VERSION 5.8 ;
BUSBITCHARS "[]" ;
DIVIDERCHAR "/" ;
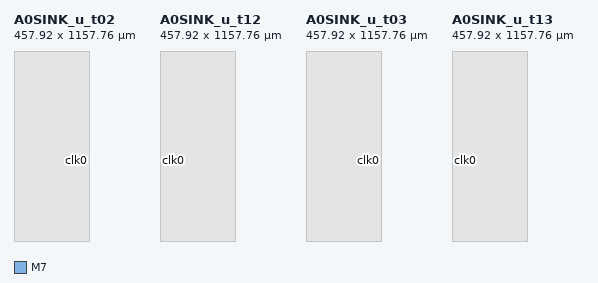
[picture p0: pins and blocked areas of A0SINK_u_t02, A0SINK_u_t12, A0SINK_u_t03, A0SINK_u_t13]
MACRO A0SINK_u_t02
  CLASS BLOCK ;
  ORIGIN 0 0 ;
  SIZE 457.920 BY 1157.760 ;
  SYMMETRY X Y ;
  PIN clk0
    DIRECTION INPUT ;
    USE CLOCK ;
    PORT
      LAYER M7 ;
        RECT 457.380 489.656 457.460 489.736 ;
    END
  END clk0
  OBS
    LAYER M1 ;
      RECT 0 0 457.920 1157.760 ;
    LAYER M2 ;
      RECT 0 0 457.920 1157.760 ;
    LAYER M3 ;
      RECT 0 0 457.920 1157.760 ;
    LAYER M4 ;
      RECT 0 0 457.920 1157.760 ;
    LAYER M5 ;
      RECT 0 0 457.920 1157.760 ;
    LAYER M6 ;
      RECT 0 0 457.920 1157.760 ;
  END
END A0SINK_u_t02
MACRO A0SINK_u_t12
  CLASS BLOCK ;
  ORIGIN 0 0 ;
  SIZE 457.920 BY 1157.760 ;
  SYMMETRY X Y ;
  PIN clk0
    DIRECTION INPUT ;
    USE CLOCK ;
    PORT
      LAYER M7 ;
        RECT 0.460 489.656 0.540 489.736 ;
    END
  END clk0
  OBS
    LAYER M1 ;
      RECT 0 0 457.920 1157.760 ;
    LAYER M2 ;
      RECT 0 0 457.920 1157.760 ;
    LAYER M3 ;
      RECT 0 0 457.920 1157.760 ;
    LAYER M4 ;
      RECT 0 0 457.920 1157.760 ;
    LAYER M5 ;
      RECT 0 0 457.920 1157.760 ;
    LAYER M6 ;
      RECT 0 0 457.920 1157.760 ;
  END
END A0SINK_u_t12
MACRO A0SINK_u_t03
  CLASS BLOCK ;
  ORIGIN 0 0 ;
  SIZE 457.920 BY 1157.760 ;
  SYMMETRY X Y ;
  PIN clk0
    DIRECTION INPUT ;
    USE CLOCK ;
    PORT
      LAYER M7 ;
        RECT 457.380 489.656 457.460 489.736 ;
    END
  END clk0
  OBS
    LAYER M1 ;
      RECT 0 0 457.920 1157.760 ;
    LAYER M2 ;
      RECT 0 0 457.920 1157.760 ;
    LAYER M3 ;
      RECT 0 0 457.920 1157.760 ;
    LAYER M4 ;
      RECT 0 0 457.920 1157.760 ;
    LAYER M5 ;
      RECT 0 0 457.920 1157.760 ;
    LAYER M6 ;
      RECT 0 0 457.920 1157.760 ;
  END
END A0SINK_u_t03
MACRO A0SINK_u_t13
  CLASS BLOCK ;
  ORIGIN 0 0 ;
  SIZE 457.920 BY 1157.760 ;
  SYMMETRY X Y ;
  PIN clk0
    DIRECTION INPUT ;
    USE CLOCK ;
    PORT
      LAYER M7 ;
        RECT 0.460 489.656 0.540 489.736 ;
    END
  END clk0
  OBS
    LAYER M1 ;
      RECT 0 0 457.920 1157.760 ;
    LAYER M2 ;
      RECT 0 0 457.920 1157.760 ;
    LAYER M3 ;
      RECT 0 0 457.920 1157.760 ;
    LAYER M4 ;
      RECT 0 0 457.920 1157.760 ;
    LAYER M5 ;
      RECT 0 0 457.920 1157.760 ;
    LAYER M6 ;
      RECT 0 0 457.920 1157.760 ;
  END
END A0SINK_u_t13
END LIBRARY
